VERSION 5.7 ;
  NOWIREEXTENSIONATPIN ON ;
  DIVIDERCHAR "/" ;
  BUSBITCHARS "[]" ;
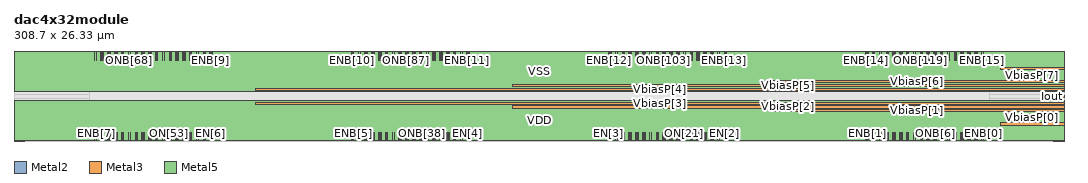
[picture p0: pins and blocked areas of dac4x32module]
MACRO dac4x32module
  CLASS BLOCK ;
  FOREIGN dac4x32module ;
  ORIGIN 0.000 0.070 ;
  SIZE 308.700 BY 26.330 ;
  PIN EN[13]
    ANTENNAGATEAREA 0.039000 ;
    PORT
      LAYER Metal2 ;
        RECT 209.325 23.715 209.525 26.190 ;
    END
  END EN[13]
  PIN ENB[13]
    ANTENNAGATEAREA 0.039000 ;
    PORT
      LAYER Metal2 ;
        RECT 208.775 23.715 208.975 26.190 ;
    END
  END ENB[13]
  PIN ON[111]
    ANTENNAGATEAREA 0.039000 ;
    PORT
      LAYER Metal2 ;
        RECT 207.325 23.715 207.525 26.190 ;
    END
  END ON[111]
  PIN ONB[111]
    ANTENNAGATEAREA 0.039000 ;
    PORT
      LAYER Metal2 ;
        RECT 206.775 23.715 206.975 26.190 ;
    END
  END ONB[111]
  PIN ON[110]
    ANTENNAGATEAREA 0.039000 ;
    PORT
      LAYER Metal2 ;
        RECT 205.325 23.715 205.525 26.190 ;
    END
  END ON[110]
  PIN ONB[110]
    ANTENNAGATEAREA 0.039000 ;
    PORT
      LAYER Metal2 ;
        RECT 204.775 23.715 204.975 26.190 ;
    END
  END ONB[110]
  PIN ON[109]
    ANTENNAGATEAREA 0.039000 ;
    PORT
      LAYER Metal2 ;
        RECT 203.325 23.715 203.525 26.190 ;
    END
  END ON[109]
  PIN ONB[109]
    ANTENNAGATEAREA 0.039000 ;
    PORT
      LAYER Metal2 ;
        RECT 202.775 23.715 202.975 26.190 ;
    END
  END ONB[109]
  PIN ON[108]
    ANTENNAGATEAREA 0.039000 ;
    PORT
      LAYER Metal2 ;
        RECT 201.325 23.715 201.525 26.190 ;
    END
  END ON[108]
  PIN ONB[108]
    ANTENNAGATEAREA 0.039000 ;
    PORT
      LAYER Metal2 ;
        RECT 200.775 23.715 200.975 26.190 ;
    END
  END ONB[108]
  PIN ON[107]
    ANTENNAGATEAREA 0.039000 ;
    PORT
      LAYER Metal2 ;
        RECT 199.325 23.715 199.525 26.190 ;
    END
  END ON[107]
  PIN ONB[107]
    ANTENNAGATEAREA 0.039000 ;
    PORT
      LAYER Metal2 ;
        RECT 198.775 23.715 198.975 26.190 ;
    END
  END ONB[107]
  PIN ON[106]
    ANTENNAGATEAREA 0.039000 ;
    PORT
      LAYER Metal2 ;
        RECT 197.325 23.715 197.525 26.190 ;
    END
  END ON[106]
  PIN ONB[106]
    ANTENNAGATEAREA 0.039000 ;
    PORT
      LAYER Metal2 ;
        RECT 196.775 23.715 196.975 26.190 ;
    END
  END ONB[106]
  PIN ON[105]
    ANTENNAGATEAREA 0.039000 ;
    PORT
      LAYER Metal2 ;
        RECT 195.325 23.715 195.525 26.190 ;
    END
  END ON[105]
  PIN ONB[105]
    ANTENNAGATEAREA 0.039000 ;
    PORT
      LAYER Metal2 ;
        RECT 194.775 23.715 194.975 26.190 ;
    END
  END ONB[105]
  PIN ON[104]
    ANTENNAGATEAREA 0.039000 ;
    PORT
      LAYER Metal2 ;
        RECT 193.325 23.715 193.525 26.190 ;
    END
  END ON[104]
  PIN ONB[104]
    ANTENNAGATEAREA 0.039000 ;
    PORT
      LAYER Metal2 ;
        RECT 192.775 23.715 192.975 26.190 ;
    END
  END ONB[104]
  PIN ON[103]
    ANTENNAGATEAREA 0.039000 ;
    PORT
      LAYER Metal2 ;
        RECT 191.325 23.715 191.525 26.190 ;
    END
  END ON[103]
  PIN ONB[103]
    ANTENNAGATEAREA 0.039000 ;
    PORT
      LAYER Metal2 ;
        RECT 190.775 23.715 190.975 26.190 ;
    END
  END ONB[103]
  PIN ON[102]
    ANTENNAGATEAREA 0.039000 ;
    PORT
      LAYER Metal2 ;
        RECT 189.325 23.715 189.525 26.190 ;
    END
  END ON[102]
  PIN ONB[102]
    ANTENNAGATEAREA 0.039000 ;
    PORT
      LAYER Metal2 ;
        RECT 188.775 23.715 188.975 26.190 ;
    END
  END ONB[102]
  PIN ON[101]
    ANTENNAGATEAREA 0.039000 ;
    PORT
      LAYER Metal2 ;
        RECT 187.325 23.715 187.525 26.190 ;
    END
  END ON[101]
  PIN ONB[101]
    ANTENNAGATEAREA 0.039000 ;
    PORT
      LAYER Metal2 ;
        RECT 186.775 23.715 186.975 26.190 ;
    END
  END ONB[101]
  PIN ON[100]
    ANTENNAGATEAREA 0.039000 ;
    PORT
      LAYER Metal2 ;
        RECT 185.325 23.715 185.525 26.190 ;
    END
  END ON[100]
  PIN ONB[100]
    ANTENNAGATEAREA 0.039000 ;
    PORT
      LAYER Metal2 ;
        RECT 184.775 23.715 184.975 26.190 ;
    END
  END ONB[100]
  PIN ON[99]
    ANTENNAGATEAREA 0.039000 ;
    PORT
      LAYER Metal2 ;
        RECT 183.325 23.715 183.525 26.190 ;
    END
  END ON[99]
  PIN ONB[99]
    ANTENNAGATEAREA 0.039000 ;
    PORT
      LAYER Metal2 ;
        RECT 182.775 23.715 182.975 26.190 ;
    END
  END ONB[99]
  PIN ON[98]
    ANTENNAGATEAREA 0.039000 ;
    PORT
      LAYER Metal2 ;
        RECT 181.325 23.715 181.525 26.190 ;
    END
  END ON[98]
  PIN ONB[98]
    ANTENNAGATEAREA 0.039000 ;
    PORT
      LAYER Metal2 ;
        RECT 180.775 23.715 180.975 26.190 ;
    END
  END ONB[98]
  PIN ON[97]
    ANTENNAGATEAREA 0.039000 ;
    PORT
      LAYER Metal2 ;
        RECT 179.325 23.715 179.525 26.190 ;
    END
  END ON[97]
  PIN ONB[97]
    ANTENNAGATEAREA 0.039000 ;
    PORT
      LAYER Metal2 ;
        RECT 178.775 23.715 178.975 26.190 ;
    END
  END ONB[97]
  PIN ON[96]
    ANTENNAGATEAREA 0.039000 ;
    PORT
      LAYER Metal2 ;
        RECT 177.325 23.715 177.525 26.190 ;
    END
  END ON[96]
  PIN ONB[96]
    ANTENNAGATEAREA 0.039000 ;
    PORT
      LAYER Metal2 ;
        RECT 176.775 23.715 176.975 26.190 ;
    END
  END ONB[96]
  PIN EN[12]
    ANTENNAGATEAREA 0.039000 ;
    PORT
      LAYER Metal2 ;
        RECT 175.325 23.715 175.525 26.190 ;
    END
  END EN[12]
  PIN ENB[12]
    ANTENNAGATEAREA 0.039000 ;
    PORT
      LAYER Metal2 ;
        RECT 174.775 23.715 174.975 26.190 ;
    END
  END ENB[12]
  PIN EN[15]
    ANTENNAGATEAREA 0.039000 ;
    PORT
      LAYER Metal2 ;
        RECT 284.925 23.715 285.125 26.190 ;
    END
  END EN[15]
  PIN ENB[15]
    ANTENNAGATEAREA 0.039000 ;
    PORT
      LAYER Metal2 ;
        RECT 284.375 23.715 284.575 26.190 ;
    END
  END ENB[15]
  PIN ON[127]
    ANTENNAGATEAREA 0.039000 ;
    PORT
      LAYER Metal2 ;
        RECT 282.925 23.715 283.125 26.190 ;
    END
  END ON[127]
  PIN ONB[127]
    ANTENNAGATEAREA 0.039000 ;
    PORT
      LAYER Metal2 ;
        RECT 282.375 23.715 282.575 26.190 ;
    END
  END ONB[127]
  PIN ON[126]
    ANTENNAGATEAREA 0.039000 ;
    PORT
      LAYER Metal2 ;
        RECT 280.925 23.715 281.125 26.190 ;
    END
  END ON[126]
  PIN ONB[126]
    ANTENNAGATEAREA 0.039000 ;
    PORT
      LAYER Metal2 ;
        RECT 280.375 23.715 280.575 26.190 ;
    END
  END ONB[126]
  PIN ON[125]
    ANTENNAGATEAREA 0.039000 ;
    PORT
      LAYER Metal2 ;
        RECT 278.925 23.715 279.125 26.190 ;
    END
  END ON[125]
  PIN ONB[125]
    ANTENNAGATEAREA 0.039000 ;
    PORT
      LAYER Metal2 ;
        RECT 278.375 23.715 278.575 26.190 ;
    END
  END ONB[125]
  PIN ON[124]
    ANTENNAGATEAREA 0.039000 ;
    PORT
      LAYER Metal2 ;
        RECT 276.925 23.715 277.125 26.190 ;
    END
  END ON[124]
  PIN ONB[124]
    ANTENNAGATEAREA 0.039000 ;
    PORT
      LAYER Metal2 ;
        RECT 276.375 23.715 276.575 26.190 ;
    END
  END ONB[124]
  PIN ON[123]
    ANTENNAGATEAREA 0.039000 ;
    PORT
      LAYER Metal2 ;
        RECT 274.925 23.715 275.125 26.190 ;
    END
  END ON[123]
  PIN ONB[123]
    ANTENNAGATEAREA 0.039000 ;
    PORT
      LAYER Metal2 ;
        RECT 274.375 23.715 274.575 26.190 ;
    END
  END ONB[123]
  PIN ON[122]
    ANTENNAGATEAREA 0.039000 ;
    PORT
      LAYER Metal2 ;
        RECT 272.925 23.715 273.125 26.190 ;
    END
  END ON[122]
  PIN ONB[122]
    ANTENNAGATEAREA 0.039000 ;
    PORT
      LAYER Metal2 ;
        RECT 272.375 23.715 272.575 26.190 ;
    END
  END ONB[122]
  PIN ON[121]
    ANTENNAGATEAREA 0.039000 ;
    PORT
      LAYER Metal2 ;
        RECT 270.925 23.715 271.125 26.190 ;
    END
  END ON[121]
  PIN ONB[121]
    ANTENNAGATEAREA 0.039000 ;
    PORT
      LAYER Metal2 ;
        RECT 270.375 23.715 270.575 26.190 ;
    END
  END ONB[121]
  PIN ON[120]
    ANTENNAGATEAREA 0.039000 ;
    PORT
      LAYER Metal2 ;
        RECT 268.925 23.715 269.125 26.190 ;
    END
  END ON[120]
  PIN ONB[120]
    ANTENNAGATEAREA 0.039000 ;
    PORT
      LAYER Metal2 ;
        RECT 268.375 23.715 268.575 26.190 ;
    END
  END ONB[120]
  PIN ON[119]
    ANTENNAGATEAREA 0.039000 ;
    PORT
      LAYER Metal2 ;
        RECT 266.925 23.715 267.125 26.190 ;
    END
  END ON[119]
  PIN ONB[119]
    ANTENNAGATEAREA 0.039000 ;
    PORT
      LAYER Metal2 ;
        RECT 266.375 23.715 266.575 26.190 ;
    END
  END ONB[119]
  PIN ON[118]
    ANTENNAGATEAREA 0.039000 ;
    PORT
      LAYER Metal2 ;
        RECT 264.925 23.715 265.125 26.190 ;
    END
  END ON[118]
  PIN ONB[118]
    ANTENNAGATEAREA 0.039000 ;
    PORT
      LAYER Metal2 ;
        RECT 264.375 23.715 264.575 26.190 ;
    END
  END ONB[118]
  PIN ON[117]
    ANTENNAGATEAREA 0.039000 ;
    PORT
      LAYER Metal2 ;
        RECT 262.925 23.715 263.125 26.190 ;
    END
  END ON[117]
  PIN ONB[117]
    ANTENNAGATEAREA 0.039000 ;
    PORT
      LAYER Metal2 ;
        RECT 262.375 23.715 262.575 26.190 ;
    END
  END ONB[117]
  PIN ON[116]
    ANTENNAGATEAREA 0.039000 ;
    PORT
      LAYER Metal2 ;
        RECT 260.925 23.715 261.125 26.190 ;
    END
  END ON[116]
  PIN ONB[116]
    ANTENNAGATEAREA 0.039000 ;
    PORT
      LAYER Metal2 ;
        RECT 260.375 23.715 260.575 26.190 ;
    END
  END ONB[116]
  PIN ON[115]
    ANTENNAGATEAREA 0.039000 ;
    PORT
      LAYER Metal2 ;
        RECT 258.925 23.715 259.125 26.190 ;
    END
  END ON[115]
  PIN ONB[115]
    ANTENNAGATEAREA 0.039000 ;
    PORT
      LAYER Metal2 ;
        RECT 258.375 23.715 258.575 26.190 ;
    END
  END ONB[115]
  PIN ON[114]
    ANTENNAGATEAREA 0.039000 ;
    PORT
      LAYER Metal2 ;
        RECT 256.925 23.715 257.125 26.190 ;
    END
  END ON[114]
  PIN ONB[114]
    ANTENNAGATEAREA 0.039000 ;
    PORT
      LAYER Metal2 ;
        RECT 256.375 23.715 256.575 26.190 ;
    END
  END ONB[114]
  PIN ON[113]
    ANTENNAGATEAREA 0.039000 ;
    PORT
      LAYER Metal2 ;
        RECT 254.925 23.715 255.125 26.190 ;
    END
  END ON[113]
  PIN ONB[113]
    ANTENNAGATEAREA 0.039000 ;
    PORT
      LAYER Metal2 ;
        RECT 254.375 23.715 254.575 26.190 ;
    END
  END ONB[113]
  PIN ON[112]
    ANTENNAGATEAREA 0.039000 ;
    PORT
      LAYER Metal2 ;
        RECT 252.925 23.715 253.125 26.190 ;
    END
  END ON[112]
  PIN ONB[112]
    ANTENNAGATEAREA 0.039000 ;
    PORT
      LAYER Metal2 ;
        RECT 252.375 23.715 252.575 26.190 ;
    END
  END ONB[112]
  PIN EN[14]
    ANTENNAGATEAREA 0.039000 ;
    PORT
      LAYER Metal2 ;
        RECT 250.925 23.715 251.125 26.190 ;
    END
  END EN[14]
  PIN ENB[14]
    ANTENNAGATEAREA 0.039000 ;
    PORT
      LAYER Metal2 ;
        RECT 250.375 23.715 250.575 26.190 ;
    END
  END ENB[14]
  PIN EN[9]
    ANTENNAGATEAREA 0.039000 ;
    PORT
      LAYER Metal2 ;
        RECT 58.125 23.715 58.325 26.190 ;
    END
  END EN[9]
  PIN ENB[9]
    ANTENNAGATEAREA 0.039000 ;
    PORT
      LAYER Metal2 ;
        RECT 57.575 23.715 57.775 26.190 ;
    END
  END ENB[9]
  PIN ON[79]
    ANTENNAGATEAREA 0.039000 ;
    PORT
      LAYER Metal2 ;
        RECT 56.125 23.715 56.325 26.190 ;
    END
  END ON[79]
  PIN ONB[79]
    ANTENNAGATEAREA 0.039000 ;
    PORT
      LAYER Metal2 ;
        RECT 55.575 23.715 55.775 26.190 ;
    END
  END ONB[79]
  PIN ON[78]
    ANTENNAGATEAREA 0.039000 ;
    PORT
      LAYER Metal2 ;
        RECT 54.125 23.715 54.325 26.190 ;
    END
  END ON[78]
  PIN ONB[78]
    ANTENNAGATEAREA 0.039000 ;
    PORT
      LAYER Metal2 ;
        RECT 53.575 23.715 53.775 26.190 ;
    END
  END ONB[78]
  PIN ON[77]
    ANTENNAGATEAREA 0.039000 ;
    PORT
      LAYER Metal2 ;
        RECT 52.125 23.715 52.325 26.190 ;
    END
  END ON[77]
  PIN ONB[77]
    ANTENNAGATEAREA 0.039000 ;
    PORT
      LAYER Metal2 ;
        RECT 51.575 23.715 51.775 26.190 ;
    END
  END ONB[77]
  PIN ON[76]
    ANTENNAGATEAREA 0.039000 ;
    PORT
      LAYER Metal2 ;
        RECT 50.125 23.715 50.325 26.190 ;
    END
  END ON[76]
  PIN ONB[76]
    ANTENNAGATEAREA 0.039000 ;
    PORT
      LAYER Metal2 ;
        RECT 49.575 23.715 49.775 26.190 ;
    END
  END ONB[76]
  PIN ON[75]
    ANTENNAGATEAREA 0.039000 ;
    PORT
      LAYER Metal2 ;
        RECT 48.125 23.715 48.325 26.190 ;
    END
  END ON[75]
  PIN ONB[75]
    ANTENNAGATEAREA 0.039000 ;
    PORT
      LAYER Metal2 ;
        RECT 47.575 23.715 47.775 26.190 ;
    END
  END ONB[75]
  PIN ON[74]
    ANTENNAGATEAREA 0.039000 ;
    PORT
      LAYER Metal2 ;
        RECT 46.125 23.715 46.325 26.190 ;
    END
  END ON[74]
  PIN ONB[74]
    ANTENNAGATEAREA 0.039000 ;
    PORT
      LAYER Metal2 ;
        RECT 45.575 23.715 45.775 26.190 ;
    END
  END ONB[74]
  PIN ON[73]
    ANTENNAGATEAREA 0.039000 ;
    PORT
      LAYER Metal2 ;
        RECT 44.125 23.715 44.325 26.190 ;
    END
  END ON[73]
  PIN ONB[73]
    ANTENNAGATEAREA 0.039000 ;
    PORT
      LAYER Metal2 ;
        RECT 43.575 23.715 43.775 26.190 ;
    END
  END ONB[73]
  PIN ON[72]
    ANTENNAGATEAREA 0.039000 ;
    PORT
      LAYER Metal2 ;
        RECT 42.125 23.715 42.325 26.190 ;
    END
  END ON[72]
  PIN ONB[72]
    ANTENNAGATEAREA 0.039000 ;
    PORT
      LAYER Metal2 ;
        RECT 41.575 23.715 41.775 26.190 ;
    END
  END ONB[72]
  PIN ON[71]
    ANTENNAGATEAREA 0.039000 ;
    PORT
      LAYER Metal2 ;
        RECT 40.125 23.715 40.325 26.190 ;
    END
  END ON[71]
  PIN ONB[71]
    ANTENNAGATEAREA 0.039000 ;
    PORT
      LAYER Metal2 ;
        RECT 39.575 23.715 39.775 26.190 ;
    END
  END ONB[71]
  PIN ON[70]
    ANTENNAGATEAREA 0.039000 ;
    PORT
      LAYER Metal2 ;
        RECT 38.125 23.715 38.325 26.190 ;
    END
  END ON[70]
  PIN ONB[70]
    ANTENNAGATEAREA 0.039000 ;
    PORT
      LAYER Metal2 ;
        RECT 37.575 23.715 37.775 26.190 ;
    END
  END ONB[70]
  PIN ON[69]
    ANTENNAGATEAREA 0.039000 ;
    PORT
      LAYER Metal2 ;
        RECT 36.125 23.715 36.325 26.190 ;
    END
  END ON[69]
  PIN ONB[69]
    ANTENNAGATEAREA 0.039000 ;
    PORT
      LAYER Metal2 ;
        RECT 35.575 23.715 35.775 26.190 ;
    END
  END ONB[69]
  PIN ON[68]
    ANTENNAGATEAREA 0.039000 ;
    PORT
      LAYER Metal2 ;
        RECT 34.125 23.715 34.325 26.190 ;
    END
  END ON[68]
  PIN ONB[68]
    ANTENNAGATEAREA 0.039000 ;
    PORT
      LAYER Metal2 ;
        RECT 33.575 23.715 33.775 26.190 ;
    END
  END ONB[68]
  PIN ON[67]
    ANTENNAGATEAREA 0.039000 ;
    PORT
      LAYER Metal2 ;
        RECT 32.125 23.715 32.325 26.190 ;
    END
  END ON[67]
  PIN ONB[67]
    ANTENNAGATEAREA 0.039000 ;
    PORT
      LAYER Metal2 ;
        RECT 31.575 23.715 31.775 26.190 ;
    END
  END ONB[67]
  PIN ON[66]
    ANTENNAGATEAREA 0.039000 ;
    PORT
      LAYER Metal2 ;
        RECT 30.125 23.715 30.325 26.190 ;
    END
  END ON[66]
  PIN ONB[66]
    ANTENNAGATEAREA 0.039000 ;
    PORT
      LAYER Metal2 ;
        RECT 29.575 23.715 29.775 26.190 ;
    END
  END ONB[66]
  PIN ON[65]
    ANTENNAGATEAREA 0.039000 ;
    PORT
      LAYER Metal2 ;
        RECT 28.125 23.715 28.325 26.190 ;
    END
  END ON[65]
  PIN ONB[65]
    ANTENNAGATEAREA 0.039000 ;
    PORT
      LAYER Metal2 ;
        RECT 27.575 23.715 27.775 26.190 ;
    END
  END ONB[65]
  PIN ON[64]
    ANTENNAGATEAREA 0.039000 ;
    PORT
      LAYER Metal2 ;
        RECT 26.125 23.715 26.325 26.190 ;
    END
  END ON[64]
  PIN ONB[64]
    ANTENNAGATEAREA 0.039000 ;
    PORT
      LAYER Metal2 ;
        RECT 25.575 23.715 25.775 26.190 ;
    END
  END ONB[64]
  PIN EN[8]
    ANTENNAGATEAREA 0.039000 ;
    PORT
      LAYER Metal2 ;
        RECT 24.125 23.715 24.325 26.190 ;
    END
  END EN[8]
  PIN ENB[8]
    ANTENNAGATEAREA 0.039000 ;
    PORT
      LAYER Metal2 ;
        RECT 23.575 23.715 23.775 26.190 ;
    END
  END ENB[8]
  PIN EN[11]
    ANTENNAGATEAREA 0.039000 ;
    PORT
      LAYER Metal2 ;
        RECT 133.725 23.715 133.925 26.190 ;
    END
  END EN[11]
  PIN ENB[11]
    ANTENNAGATEAREA 0.039000 ;
    PORT
      LAYER Metal2 ;
        RECT 133.175 23.715 133.375 26.190 ;
    END
  END ENB[11]
  PIN ON[95]
    ANTENNAGATEAREA 0.039000 ;
    PORT
      LAYER Metal2 ;
        RECT 131.725 23.715 131.925 26.190 ;
    END
  END ON[95]
  PIN ONB[95]
    ANTENNAGATEAREA 0.039000 ;
    PORT
      LAYER Metal2 ;
        RECT 131.175 23.715 131.375 26.190 ;
    END
  END ONB[95]
  PIN ON[94]
    ANTENNAGATEAREA 0.039000 ;
    PORT
      LAYER Metal2 ;
        RECT 129.725 23.715 129.925 26.190 ;
    END
  END ON[94]
  PIN ONB[94]
    ANTENNAGATEAREA 0.039000 ;
    PORT
      LAYER Metal2 ;
        RECT 129.175 23.715 129.375 26.190 ;
    END
  END ONB[94]
  PIN ON[93]
    ANTENNAGATEAREA 0.039000 ;
    PORT
      LAYER Metal2 ;
        RECT 127.725 23.715 127.925 26.190 ;
    END
  END ON[93]
  PIN ONB[93]
    ANTENNAGATEAREA 0.039000 ;
    PORT
      LAYER Metal2 ;
        RECT 127.175 23.715 127.375 26.190 ;
    END
  END ONB[93]
  PIN ON[92]
    ANTENNAGATEAREA 0.039000 ;
    PORT
      LAYER Metal2 ;
        RECT 125.725 23.715 125.925 26.190 ;
    END
  END ON[92]
  PIN ONB[92]
    ANTENNAGATEAREA 0.039000 ;
    PORT
      LAYER Metal2 ;
        RECT 125.175 23.715 125.375 26.190 ;
    END
  END ONB[92]
  PIN ON[91]
    ANTENNAGATEAREA 0.039000 ;
    PORT
      LAYER Metal2 ;
        RECT 123.725 23.715 123.925 26.190 ;
    END
  END ON[91]
  PIN ONB[91]
    ANTENNAGATEAREA 0.039000 ;
    PORT
      LAYER Metal2 ;
        RECT 123.175 23.715 123.375 26.190 ;
    END
  END ONB[91]
  PIN ON[90]
    ANTENNAGATEAREA 0.039000 ;
    PORT
      LAYER Metal2 ;
        RECT 121.725 23.715 121.925 26.190 ;
    END
  END ON[90]
  PIN ONB[90]
    ANTENNAGATEAREA 0.039000 ;
    PORT
      LAYER Metal2 ;
        RECT 121.175 23.715 121.375 26.190 ;
    END
  END ONB[90]
  PIN ON[89]
    ANTENNAGATEAREA 0.039000 ;
    PORT
      LAYER Metal2 ;
        RECT 119.725 23.715 119.925 26.190 ;
    END
  END ON[89]
  PIN ONB[89]
    ANTENNAGATEAREA 0.039000 ;
    PORT
      LAYER Metal2 ;
        RECT 119.175 23.715 119.375 26.190 ;
    END
  END ONB[89]
  PIN ON[88]
    ANTENNAGATEAREA 0.039000 ;
    PORT
      LAYER Metal2 ;
        RECT 117.725 23.715 117.925 26.190 ;
    END
  END ON[88]
  PIN ONB[88]
    ANTENNAGATEAREA 0.039000 ;
    PORT
      LAYER Metal2 ;
        RECT 117.175 23.715 117.375 26.190 ;
    END
  END ONB[88]
  PIN ON[87]
    ANTENNAGATEAREA 0.039000 ;
    PORT
      LAYER Metal2 ;
        RECT 115.725 23.715 115.925 26.190 ;
    END
  END ON[87]
  PIN ONB[87]
    ANTENNAGATEAREA 0.039000 ;
    PORT
      LAYER Metal2 ;
        RECT 115.175 23.715 115.375 26.190 ;
    END
  END ONB[87]
  PIN ON[86]
    ANTENNAGATEAREA 0.039000 ;
    PORT
      LAYER Metal2 ;
        RECT 113.725 23.715 113.925 26.190 ;
    END
  END ON[86]
  PIN ONB[86]
    ANTENNAGATEAREA 0.039000 ;
    PORT
      LAYER Metal2 ;
        RECT 113.175 23.715 113.375 26.190 ;
    END
  END ONB[86]
  PIN ON[85]
    ANTENNAGATEAREA 0.039000 ;
    PORT
      LAYER Metal2 ;
        RECT 111.725 23.715 111.925 26.190 ;
    END
  END ON[85]
  PIN ONB[85]
    ANTENNAGATEAREA 0.039000 ;
    PORT
      LAYER Metal2 ;
        RECT 111.175 23.715 111.375 26.190 ;
    END
  END ONB[85]
  PIN ON[84]
    ANTENNAGATEAREA 0.039000 ;
    PORT
      LAYER Metal2 ;
        RECT 109.725 23.715 109.925 26.190 ;
    END
  END ON[84]
  PIN ONB[84]
    ANTENNAGATEAREA 0.039000 ;
    PORT
      LAYER Metal2 ;
        RECT 109.175 23.715 109.375 26.190 ;
    END
  END ONB[84]
  PIN ON[83]
    ANTENNAGATEAREA 0.039000 ;
    PORT
      LAYER Metal2 ;
        RECT 107.725 23.715 107.925 26.190 ;
    END
  END ON[83]
  PIN ONB[83]
    ANTENNAGATEAREA 0.039000 ;
    PORT
      LAYER Metal2 ;
        RECT 107.175 23.715 107.375 26.190 ;
    END
  END ONB[83]
  PIN ON[82]
    ANTENNAGATEAREA 0.039000 ;
    PORT
      LAYER Metal2 ;
        RECT 105.725 23.715 105.925 26.190 ;
    END
  END ON[82]
  PIN ONB[82]
    ANTENNAGATEAREA 0.039000 ;
    PORT
      LAYER Metal2 ;
        RECT 105.175 23.715 105.375 26.190 ;
    END
  END ONB[82]
  PIN ON[81]
    ANTENNAGATEAREA 0.039000 ;
    PORT
      LAYER Metal2 ;
        RECT 103.725 23.715 103.925 26.190 ;
    END
  END ON[81]
  PIN ONB[81]
    ANTENNAGATEAREA 0.039000 ;
    PORT
      LAYER Metal2 ;
        RECT 103.175 23.715 103.375 26.190 ;
    END
  END ONB[81]
  PIN ON[80]
    ANTENNAGATEAREA 0.039000 ;
    PORT
      LAYER Metal2 ;
        RECT 101.725 23.715 101.925 26.190 ;
    END
  END ON[80]
  PIN ONB[80]
    ANTENNAGATEAREA 0.039000 ;
    PORT
      LAYER Metal2 ;
        RECT 101.175 23.715 101.375 26.190 ;
    END
  END ONB[80]
  PIN EN[10]
    ANTENNAGATEAREA 0.039000 ;
    PORT
      LAYER Metal2 ;
        RECT 99.725 23.715 99.925 26.190 ;
    END
  END EN[10]
  PIN ENB[10]
    ANTENNAGATEAREA 0.039000 ;
    PORT
      LAYER Metal2 ;
        RECT 99.175 23.715 99.375 26.190 ;
    END
  END ENB[10]
  PIN EN[4]
    ANTENNAGATEAREA 0.039000 ;
    PORT
      LAYER Metal2 ;
        RECT 133.175 0.000 133.375 2.475 ;
    END
  END EN[4]
  PIN ENB[4]
    ANTENNAGATEAREA 0.039000 ;
    PORT
      LAYER Metal2 ;
        RECT 133.725 0.000 133.925 2.475 ;
    END
  END ENB[4]
  PIN EN[6]
    ANTENNAGATEAREA 0.039000 ;
    PORT
      LAYER Metal2 ;
        RECT 57.575 0.000 57.775 2.475 ;
    END
  END EN[6]
  PIN ENB[6]
    ANTENNAGATEAREA 0.039000 ;
    PORT
      LAYER Metal2 ;
        RECT 58.125 0.000 58.325 2.475 ;
    END
  END ENB[6]
  PIN ON[63]
    ANTENNAGATEAREA 0.039000 ;
    PORT
      LAYER Metal2 ;
        RECT 25.575 0.000 25.775 2.475 ;
    END
  END ON[63]
  PIN ONB[63]
    ANTENNAGATEAREA 0.039000 ;
    PORT
      LAYER Metal2 ;
        RECT 26.125 0.000 26.325 2.475 ;
    END
  END ONB[63]
  PIN ON[62]
    ANTENNAGATEAREA 0.039000 ;
    PORT
      LAYER Metal2 ;
        RECT 27.575 0.000 27.775 2.475 ;
    END
  END ON[62]
  PIN ONB[62]
    ANTENNAGATEAREA 0.039000 ;
    PORT
      LAYER Metal2 ;
        RECT 28.125 0.000 28.325 2.475 ;
    END
  END ONB[62]
  PIN ON[61]
    ANTENNAGATEAREA 0.039000 ;
    PORT
      LAYER Metal2 ;
        RECT 29.575 0.000 29.775 2.475 ;
    END
  END ON[61]
  PIN ONB[61]
    ANTENNAGATEAREA 0.039000 ;
    PORT
      LAYER Metal2 ;
        RECT 30.125 0.000 30.325 2.475 ;
    END
  END ONB[61]
  PIN ON[60]
    ANTENNAGATEAREA 0.039000 ;
    PORT
      LAYER Metal2 ;
        RECT 31.575 0.000 31.775 2.475 ;
    END
  END ON[60]
  PIN ONB[60]
    ANTENNAGATEAREA 0.039000 ;
    PORT
      LAYER Metal2 ;
        RECT 32.125 0.000 32.325 2.475 ;
    END
  END ONB[60]
  PIN ON[59]
    ANTENNAGATEAREA 0.039000 ;
    PORT
      LAYER Metal2 ;
        RECT 33.575 0.000 33.775 2.475 ;
    END
  END ON[59]
  PIN ONB[59]
    ANTENNAGATEAREA 0.039000 ;
    PORT
      LAYER Metal2 ;
        RECT 34.125 0.000 34.325 2.475 ;
    END
  END ONB[59]
  PIN ON[58]
    ANTENNAGATEAREA 0.039000 ;
    PORT
      LAYER Metal2 ;
        RECT 35.575 0.000 35.775 2.475 ;
    END
  END ON[58]
  PIN ONB[58]
    ANTENNAGATEAREA 0.039000 ;
    PORT
      LAYER Metal2 ;
        RECT 36.125 0.000 36.325 2.475 ;
    END
  END ONB[58]
  PIN ON[57]
    ANTENNAGATEAREA 0.039000 ;
    PORT
      LAYER Metal2 ;
        RECT 37.575 0.000 37.775 2.475 ;
    END
  END ON[57]
  PIN EN[7]
    ANTENNAGATEAREA 0.039000 ;
    PORT
      LAYER Metal2 ;
        RECT 23.575 0.000 23.775 2.475 ;
    END
  END EN[7]
  PIN ENB[7]
    ANTENNAGATEAREA 0.039000 ;
    PORT
      LAYER Metal2 ;
        RECT 24.125 0.000 24.325 2.475 ;
    END
  END ENB[7]
  PIN ONB[57]
    ANTENNAGATEAREA 0.039000 ;
    PORT
      LAYER Metal2 ;
        RECT 38.125 0.000 38.325 2.475 ;
    END
  END ONB[57]
  PIN ON[56]
    ANTENNAGATEAREA 0.039000 ;
    PORT
      LAYER Metal2 ;
        RECT 39.575 0.000 39.775 2.475 ;
    END
  END ON[56]
  PIN ONB[56]
    ANTENNAGATEAREA 0.039000 ;
    PORT
      LAYER Metal2 ;
        RECT 40.125 0.000 40.325 2.475 ;
    END
  END ONB[56]
  PIN ON[55]
    ANTENNAGATEAREA 0.039000 ;
    PORT
      LAYER Metal2 ;
        RECT 41.575 0.000 41.775 2.475 ;
    END
  END ON[55]
  PIN ONB[55]
    ANTENNAGATEAREA 0.039000 ;
    PORT
      LAYER Metal2 ;
        RECT 42.125 0.000 42.325 2.475 ;
    END
  END ONB[55]
  PIN ON[54]
    ANTENNAGATEAREA 0.039000 ;
    PORT
      LAYER Metal2 ;
        RECT 43.575 0.000 43.775 2.475 ;
    END
  END ON[54]
  PIN ONB[54]
    ANTENNAGATEAREA 0.039000 ;
    PORT
      LAYER Metal2 ;
        RECT 44.125 0.000 44.325 2.475 ;
    END
  END ONB[54]
  PIN ON[53]
    ANTENNAGATEAREA 0.039000 ;
    PORT
      LAYER Metal2 ;
        RECT 45.575 0.000 45.775 2.475 ;
    END
  END ON[53]
  PIN ONB[53]
    ANTENNAGATEAREA 0.039000 ;
    PORT
      LAYER Metal2 ;
        RECT 46.125 0.000 46.325 2.475 ;
    END
  END ONB[53]
  PIN ON[52]
    ANTENNAGATEAREA 0.039000 ;
    PORT
      LAYER Metal2 ;
        RECT 47.575 0.000 47.775 2.475 ;
    END
  END ON[52]
  PIN ONB[52]
    ANTENNAGATEAREA 0.039000 ;
    PORT
      LAYER Metal2 ;
        RECT 48.125 0.000 48.325 2.475 ;
    END
  END ONB[52]
  PIN ON[51]
    ANTENNAGATEAREA 0.039000 ;
    PORT
      LAYER Metal2 ;
        RECT 49.575 0.000 49.775 2.475 ;
    END
  END ON[51]
  PIN ONB[51]
    ANTENNAGATEAREA 0.039000 ;
    PORT
      LAYER Metal2 ;
        RECT 50.125 0.000 50.325 2.475 ;
    END
  END ONB[51]
  PIN ON[50]
    ANTENNAGATEAREA 0.039000 ;
    PORT
      LAYER Metal2 ;
        RECT 51.575 0.000 51.775 2.475 ;
    END
  END ON[50]
  PIN ONB[50]
    ANTENNAGATEAREA 0.039000 ;
    PORT
      LAYER Metal2 ;
        RECT 52.125 0.000 52.325 2.475 ;
    END
  END ONB[50]
  PIN ON[49]
    ANTENNAGATEAREA 0.039000 ;
    PORT
      LAYER Metal2 ;
        RECT 53.575 0.000 53.775 2.475 ;
    END
  END ON[49]
  PIN ONB[49]
    ANTENNAGATEAREA 0.039000 ;
    PORT
      LAYER Metal2 ;
        RECT 54.125 0.000 54.325 2.475 ;
    END
  END ONB[49]
  PIN ON[48]
    ANTENNAGATEAREA 0.039000 ;
    PORT
      LAYER Metal2 ;
        RECT 55.575 0.000 55.775 2.475 ;
    END
  END ON[48]
  PIN ONB[48]
    ANTENNAGATEAREA 0.039000 ;
    PORT
      LAYER Metal2 ;
        RECT 56.125 0.000 56.325 2.475 ;
    END
  END ONB[48]
  PIN ON[47]
    ANTENNAGATEAREA 0.039000 ;
    PORT
      LAYER Metal2 ;
        RECT 101.175 0.000 101.375 2.475 ;
    END
  END ON[47]
  PIN ONB[47]
    ANTENNAGATEAREA 0.039000 ;
    PORT
      LAYER Metal2 ;
        RECT 101.725 0.000 101.925 2.475 ;
    END
  END ONB[47]
  PIN ON[46]
    ANTENNAGATEAREA 0.039000 ;
    PORT
      LAYER Metal2 ;
        RECT 103.175 0.000 103.375 2.475 ;
    END
  END ON[46]
  PIN ONB[46]
    ANTENNAGATEAREA 0.039000 ;
    PORT
      LAYER Metal2 ;
        RECT 103.725 0.000 103.925 2.475 ;
    END
  END ONB[46]
  PIN ON[45]
    ANTENNAGATEAREA 0.039000 ;
    PORT
      LAYER Metal2 ;
        RECT 105.175 0.000 105.375 2.475 ;
    END
  END ON[45]
  PIN ONB[45]
    ANTENNAGATEAREA 0.039000 ;
    PORT
      LAYER Metal2 ;
        RECT 105.725 0.000 105.925 2.475 ;
    END
  END ONB[45]
  PIN ON[44]
    ANTENNAGATEAREA 0.039000 ;
    PORT
      LAYER Metal2 ;
        RECT 107.175 0.000 107.375 2.475 ;
    END
  END ON[44]
  PIN ONB[44]
    ANTENNAGATEAREA 0.039000 ;
    PORT
      LAYER Metal2 ;
        RECT 107.725 0.000 107.925 2.475 ;
    END
  END ONB[44]
  PIN ON[43]
    ANTENNAGATEAREA 0.039000 ;
    PORT
      LAYER Metal2 ;
        RECT 109.175 0.000 109.375 2.475 ;
    END
  END ON[43]
  PIN ONB[43]
    ANTENNAGATEAREA 0.039000 ;
    PORT
      LAYER Metal2 ;
        RECT 109.725 0.000 109.925 2.475 ;
    END
  END ONB[43]
  PIN ON[42]
    ANTENNAGATEAREA 0.039000 ;
    PORT
      LAYER Metal2 ;
        RECT 111.175 0.000 111.375 2.475 ;
    END
  END ON[42]
  PIN ONB[42]
    ANTENNAGATEAREA 0.039000 ;
    PORT
      LAYER Metal2 ;
        RECT 111.725 0.000 111.925 2.475 ;
    END
  END ONB[42]
  PIN ON[41]
    ANTENNAGATEAREA 0.039000 ;
    PORT
      LAYER Metal2 ;
        RECT 113.175 0.000 113.375 2.475 ;
    END
  END ON[41]
  PIN EN[5]
    ANTENNAGATEAREA 0.039000 ;
    PORT
      LAYER Metal2 ;
        RECT 99.175 0.000 99.375 2.475 ;
    END
  END EN[5]
  PIN ENB[5]
    ANTENNAGATEAREA 0.039000 ;
    PORT
      LAYER Metal2 ;
        RECT 99.725 0.000 99.925 2.475 ;
    END
  END ENB[5]
  PIN ONB[41]
    ANTENNAGATEAREA 0.039000 ;
    PORT
      LAYER Metal2 ;
        RECT 113.725 0.000 113.925 2.475 ;
    END
  END ONB[41]
  PIN ON[40]
    ANTENNAGATEAREA 0.039000 ;
    PORT
      LAYER Metal2 ;
        RECT 115.175 0.000 115.375 2.475 ;
    END
  END ON[40]
  PIN ONB[40]
    ANTENNAGATEAREA 0.039000 ;
    PORT
      LAYER Metal2 ;
        RECT 115.725 0.000 115.925 2.475 ;
    END
  END ONB[40]
  PIN ON[39]
    ANTENNAGATEAREA 0.039000 ;
    PORT
      LAYER Metal2 ;
        RECT 117.175 0.000 117.375 2.475 ;
    END
  END ON[39]
  PIN ONB[39]
    ANTENNAGATEAREA 0.039000 ;
    PORT
      LAYER Metal2 ;
        RECT 117.725 0.000 117.925 2.475 ;
    END
  END ONB[39]
  PIN ON[38]
    ANTENNAGATEAREA 0.039000 ;
    PORT
      LAYER Metal2 ;
        RECT 119.175 0.000 119.375 2.475 ;
    END
  END ON[38]
  PIN ONB[38]
    ANTENNAGATEAREA 0.039000 ;
    PORT
      LAYER Metal2 ;
        RECT 119.725 0.000 119.925 2.475 ;
    END
  END ONB[38]
  PIN ON[37]
    ANTENNAGATEAREA 0.039000 ;
    PORT
      LAYER Metal2 ;
        RECT 121.175 0.000 121.375 2.475 ;
    END
  END ON[37]
  PIN ONB[37]
    ANTENNAGATEAREA 0.039000 ;
    PORT
      LAYER Metal2 ;
        RECT 121.725 0.000 121.925 2.475 ;
    END
  END ONB[37]
  PIN ON[36]
    ANTENNAGATEAREA 0.039000 ;
    PORT
      LAYER Metal2 ;
        RECT 123.175 0.000 123.375 2.475 ;
    END
  END ON[36]
  PIN ONB[36]
    ANTENNAGATEAREA 0.039000 ;
    PORT
      LAYER Metal2 ;
        RECT 123.725 0.000 123.925 2.475 ;
    END
  END ONB[36]
  PIN ON[35]
    ANTENNAGATEAREA 0.039000 ;
    PORT
      LAYER Metal2 ;
        RECT 125.175 0.000 125.375 2.475 ;
    END
  END ON[35]
  PIN ONB[35]
    ANTENNAGATEAREA 0.039000 ;
    PORT
      LAYER Metal2 ;
        RECT 125.725 0.000 125.925 2.475 ;
    END
  END ONB[35]
  PIN ON[34]
    ANTENNAGATEAREA 0.039000 ;
    PORT
      LAYER Metal2 ;
        RECT 127.175 0.000 127.375 2.475 ;
    END
  END ON[34]
  PIN ONB[34]
    ANTENNAGATEAREA 0.039000 ;
    PORT
      LAYER Metal2 ;
        RECT 127.725 0.000 127.925 2.475 ;
    END
  END ONB[34]
  PIN ON[33]
    ANTENNAGATEAREA 0.039000 ;
    PORT
      LAYER Metal2 ;
        RECT 129.175 0.000 129.375 2.475 ;
    END
  END ON[33]
  PIN ONB[33]
    ANTENNAGATEAREA 0.039000 ;
    PORT
      LAYER Metal2 ;
        RECT 129.725 0.000 129.925 2.475 ;
    END
  END ONB[33]
  PIN ON[32]
    ANTENNAGATEAREA 0.039000 ;
    PORT
      LAYER Metal2 ;
        RECT 131.175 0.000 131.375 2.475 ;
    END
  END ON[32]
  PIN ONB[32]
    ANTENNAGATEAREA 0.039000 ;
    PORT
      LAYER Metal2 ;
        RECT 131.725 0.000 131.925 2.475 ;
    END
  END ONB[32]
  PIN EN[0]
    ANTENNAGATEAREA 0.039000 ;
    PORT
      LAYER Metal2 ;
        RECT 284.375 0.000 284.575 2.475 ;
    END
  END EN[0]
  PIN ENB[0]
    ANTENNAGATEAREA 0.039000 ;
    PORT
      LAYER Metal2 ;
        RECT 284.925 0.000 285.125 2.475 ;
    END
  END ENB[0]
  PIN EN[2]
    ANTENNAGATEAREA 0.039000 ;
    PORT
      LAYER Metal2 ;
        RECT 208.775 0.000 208.975 2.475 ;
    END
  END EN[2]
  PIN ENB[2]
    ANTENNAGATEAREA 0.039000 ;
    PORT
      LAYER Metal2 ;
        RECT 209.325 0.000 209.525 2.475 ;
    END
  END ENB[2]
  PIN ON[31]
    ANTENNAGATEAREA 0.039000 ;
    PORT
      LAYER Metal2 ;
        RECT 176.775 0.000 176.975 2.475 ;
    END
  END ON[31]
  PIN ONB[31]
    ANTENNAGATEAREA 0.039000 ;
    PORT
      LAYER Metal2 ;
        RECT 177.325 0.000 177.525 2.475 ;
    END
  END ONB[31]
  PIN ON[30]
    ANTENNAGATEAREA 0.039000 ;
    PORT
      LAYER Metal2 ;
        RECT 178.775 0.000 178.975 2.475 ;
    END
  END ON[30]
  PIN ONB[30]
    ANTENNAGATEAREA 0.039000 ;
    PORT
      LAYER Metal2 ;
        RECT 179.325 0.000 179.525 2.475 ;
    END
  END ONB[30]
  PIN ON[29]
    ANTENNAGATEAREA 0.039000 ;
    PORT
      LAYER Metal2 ;
        RECT 180.775 0.000 180.975 2.475 ;
    END
  END ON[29]
  PIN ONB[29]
    ANTENNAGATEAREA 0.039000 ;
    PORT
      LAYER Metal2 ;
        RECT 181.325 0.000 181.525 2.475 ;
    END
  END ONB[29]
  PIN ON[28]
    ANTENNAGATEAREA 0.039000 ;
    PORT
      LAYER Metal2 ;
        RECT 182.775 0.000 182.975 2.475 ;
    END
  END ON[28]
  PIN ONB[28]
    ANTENNAGATEAREA 0.039000 ;
    PORT
      LAYER Metal2 ;
        RECT 183.325 0.000 183.525 2.475 ;
    END
  END ONB[28]
  PIN ON[27]
    ANTENNAGATEAREA 0.039000 ;
    PORT
      LAYER Metal2 ;
        RECT 184.775 0.000 184.975 2.475 ;
    END
  END ON[27]
  PIN ONB[27]
    ANTENNAGATEAREA 0.039000 ;
    PORT
      LAYER Metal2 ;
        RECT 185.325 0.000 185.525 2.475 ;
    END
  END ONB[27]
  PIN ON[26]
    ANTENNAGATEAREA 0.039000 ;
    PORT
      LAYER Metal2 ;
        RECT 186.775 0.000 186.975 2.475 ;
    END
  END ON[26]
  PIN ONB[26]
    ANTENNAGATEAREA 0.039000 ;
    PORT
      LAYER Metal2 ;
        RECT 187.325 0.000 187.525 2.475 ;
    END
  END ONB[26]
  PIN ON[25]
    ANTENNAGATEAREA 0.039000 ;
    PORT
      LAYER Metal2 ;
        RECT 188.775 0.000 188.975 2.475 ;
    END
  END ON[25]
  PIN EN[3]
    ANTENNAGATEAREA 0.039000 ;
    PORT
      LAYER Metal2 ;
        RECT 174.775 0.000 174.975 2.475 ;
    END
  END EN[3]
  PIN ENB[3]
    ANTENNAGATEAREA 0.039000 ;
    PORT
      LAYER Metal2 ;
        RECT 175.325 0.000 175.525 2.475 ;
    END
  END ENB[3]
  PIN ONB[25]
    ANTENNAGATEAREA 0.039000 ;
    PORT
      LAYER Metal2 ;
        RECT 189.325 0.000 189.525 2.475 ;
    END
  END ONB[25]
  PIN ON[24]
    ANTENNAGATEAREA 0.039000 ;
    PORT
      LAYER Metal2 ;
        RECT 190.775 0.000 190.975 2.475 ;
    END
  END ON[24]
  PIN ONB[24]
    ANTENNAGATEAREA 0.039000 ;
    PORT
      LAYER Metal2 ;
        RECT 191.325 0.000 191.525 2.475 ;
    END
  END ONB[24]
  PIN ON[23]
    ANTENNAGATEAREA 0.039000 ;
    PORT
      LAYER Metal2 ;
        RECT 192.775 0.000 192.975 2.475 ;
    END
  END ON[23]
  PIN ONB[23]
    ANTENNAGATEAREA 0.039000 ;
    PORT
      LAYER Metal2 ;
        RECT 193.325 0.000 193.525 2.475 ;
    END
  END ONB[23]
  PIN ON[22]
    ANTENNAGATEAREA 0.039000 ;
    PORT
      LAYER Metal2 ;
        RECT 194.775 0.000 194.975 2.475 ;
    END
  END ON[22]
  PIN ONB[22]
    ANTENNAGATEAREA 0.039000 ;
    PORT
      LAYER Metal2 ;
        RECT 195.325 0.000 195.525 2.475 ;
    END
  END ONB[22]
  PIN ON[21]
    ANTENNAGATEAREA 0.039000 ;
    PORT
      LAYER Metal2 ;
        RECT 196.775 0.000 196.975 2.475 ;
    END
  END ON[21]
  PIN ONB[21]
    ANTENNAGATEAREA 0.039000 ;
    PORT
      LAYER Metal2 ;
        RECT 197.325 0.000 197.525 2.475 ;
    END
  END ONB[21]
  PIN ON[20]
    ANTENNAGATEAREA 0.039000 ;
    PORT
      LAYER Metal2 ;
        RECT 198.775 0.000 198.975 2.475 ;
    END
  END ON[20]
  PIN ONB[20]
    ANTENNAGATEAREA 0.039000 ;
    PORT
      LAYER Metal2 ;
        RECT 199.325 0.000 199.525 2.475 ;
    END
  END ONB[20]
  PIN ON[19]
    ANTENNAGATEAREA 0.039000 ;
    PORT
      LAYER Metal2 ;
        RECT 200.775 0.000 200.975 2.475 ;
    END
  END ON[19]
  PIN ONB[19]
    ANTENNAGATEAREA 0.039000 ;
    PORT
      LAYER Metal2 ;
        RECT 201.325 0.000 201.525 2.475 ;
    END
  END ONB[19]
  PIN ON[18]
    ANTENNAGATEAREA 0.039000 ;
    PORT
      LAYER Metal2 ;
        RECT 202.775 0.000 202.975 2.475 ;
    END
  END ON[18]
  PIN ONB[18]
    ANTENNAGATEAREA 0.039000 ;
    PORT
      LAYER Metal2 ;
        RECT 203.325 0.000 203.525 2.475 ;
    END
  END ONB[18]
  PIN ON[17]
    ANTENNAGATEAREA 0.039000 ;
    PORT
      LAYER Metal2 ;
        RECT 204.775 0.000 204.975 2.475 ;
    END
  END ON[17]
  PIN ONB[17]
    ANTENNAGATEAREA 0.039000 ;
    PORT
      LAYER Metal2 ;
        RECT 205.325 0.000 205.525 2.475 ;
    END
  END ONB[17]
  PIN ON[16]
    ANTENNAGATEAREA 0.039000 ;
    PORT
      LAYER Metal2 ;
        RECT 206.775 0.000 206.975 2.475 ;
    END
  END ON[16]
  PIN ONB[16]
    ANTENNAGATEAREA 0.039000 ;
    PORT
      LAYER Metal2 ;
        RECT 207.325 0.000 207.525 2.475 ;
    END
  END ONB[16]
  PIN ON[15]
    ANTENNAGATEAREA 0.039000 ;
    PORT
      LAYER Metal2 ;
        RECT 252.375 0.000 252.575 2.475 ;
    END
  END ON[15]
  PIN ONB[15]
    ANTENNAGATEAREA 0.039000 ;
    PORT
      LAYER Metal2 ;
        RECT 252.925 0.000 253.125 2.475 ;
    END
  END ONB[15]
  PIN ON[14]
    ANTENNAGATEAREA 0.039000 ;
    PORT
      LAYER Metal2 ;
        RECT 254.375 0.000 254.575 2.475 ;
    END
  END ON[14]
  PIN ONB[14]
    ANTENNAGATEAREA 0.039000 ;
    PORT
      LAYER Metal2 ;
        RECT 254.925 0.000 255.125 2.475 ;
    END
  END ONB[14]
  PIN ON[13]
    ANTENNAGATEAREA 0.039000 ;
    PORT
      LAYER Metal2 ;
        RECT 256.375 0.000 256.575 2.475 ;
    END
  END ON[13]
  PIN ONB[13]
    ANTENNAGATEAREA 0.039000 ;
    PORT
      LAYER Metal2 ;
        RECT 256.925 0.000 257.125 2.475 ;
    END
  END ONB[13]
  PIN ON[12]
    ANTENNAGATEAREA 0.039000 ;
    PORT
      LAYER Metal2 ;
        RECT 258.375 0.000 258.575 2.475 ;
    END
  END ON[12]
  PIN ONB[12]
    ANTENNAGATEAREA 0.039000 ;
    PORT
      LAYER Metal2 ;
        RECT 258.925 0.000 259.125 2.475 ;
    END
  END ONB[12]
  PIN ON[11]
    ANTENNAGATEAREA 0.039000 ;
    PORT
      LAYER Metal2 ;
        RECT 260.375 0.000 260.575 2.475 ;
    END
  END ON[11]
  PIN ONB[11]
    ANTENNAGATEAREA 0.039000 ;
    PORT
      LAYER Metal2 ;
        RECT 260.925 0.000 261.125 2.475 ;
    END
  END ONB[11]
  PIN ON[10]
    ANTENNAGATEAREA 0.039000 ;
    PORT
      LAYER Metal2 ;
        RECT 262.375 0.000 262.575 2.475 ;
    END
  END ON[10]
  PIN ONB[10]
    ANTENNAGATEAREA 0.039000 ;
    PORT
      LAYER Metal2 ;
        RECT 262.925 0.000 263.125 2.475 ;
    END
  END ONB[10]
  PIN ON[9]
    ANTENNAGATEAREA 0.039000 ;
    PORT
      LAYER Metal2 ;
        RECT 264.375 0.000 264.575 2.475 ;
    END
  END ON[9]
  PIN EN[1]
    ANTENNAGATEAREA 0.039000 ;
    PORT
      LAYER Metal2 ;
        RECT 250.375 0.000 250.575 2.475 ;
    END
  END EN[1]
  PIN ENB[1]
    ANTENNAGATEAREA 0.039000 ;
    PORT
      LAYER Metal2 ;
        RECT 250.925 0.000 251.125 2.475 ;
    END
  END ENB[1]
  PIN ONB[9]
    ANTENNAGATEAREA 0.039000 ;
    PORT
      LAYER Metal2 ;
        RECT 264.925 0.000 265.125 2.475 ;
    END
  END ONB[9]
  PIN ON[8]
    ANTENNAGATEAREA 0.039000 ;
    PORT
      LAYER Metal2 ;
        RECT 266.375 0.000 266.575 2.475 ;
    END
  END ON[8]
  PIN ONB[8]
    ANTENNAGATEAREA 0.039000 ;
    PORT
      LAYER Metal2 ;
        RECT 266.925 0.000 267.125 2.475 ;
    END
  END ONB[8]
  PIN ON[7]
    ANTENNAGATEAREA 0.039000 ;
    PORT
      LAYER Metal2 ;
        RECT 268.375 0.000 268.575 2.475 ;
    END
  END ON[7]
  PIN ONB[7]
    ANTENNAGATEAREA 0.039000 ;
    PORT
      LAYER Metal2 ;
        RECT 268.925 0.000 269.125 2.475 ;
    END
  END ONB[7]
  PIN ON[6]
    ANTENNAGATEAREA 0.039000 ;
    PORT
      LAYER Metal2 ;
        RECT 270.375 0.000 270.575 2.475 ;
    END
  END ON[6]
  PIN ONB[6]
    ANTENNAGATEAREA 0.039000 ;
    PORT
      LAYER Metal2 ;
        RECT 270.925 0.000 271.125 2.475 ;
    END
  END ONB[6]
  PIN ON[5]
    ANTENNAGATEAREA 0.039000 ;
    PORT
      LAYER Metal2 ;
        RECT 272.375 0.000 272.575 2.475 ;
    END
  END ON[5]
  PIN ONB[5]
    ANTENNAGATEAREA 0.039000 ;
    PORT
      LAYER Metal2 ;
        RECT 272.925 0.000 273.125 2.475 ;
    END
  END ONB[5]
  PIN ON[4]
    ANTENNAGATEAREA 0.039000 ;
    PORT
      LAYER Metal2 ;
        RECT 274.375 0.000 274.575 2.475 ;
    END
  END ON[4]
  PIN ONB[4]
    ANTENNAGATEAREA 0.039000 ;
    PORT
      LAYER Metal2 ;
        RECT 274.925 0.000 275.125 2.475 ;
    END
  END ONB[4]
  PIN ON[3]
    ANTENNAGATEAREA 0.039000 ;
    PORT
      LAYER Metal2 ;
        RECT 276.375 0.000 276.575 2.475 ;
    END
  END ON[3]
  PIN ONB[3]
    ANTENNAGATEAREA 0.039000 ;
    PORT
      LAYER Metal2 ;
        RECT 276.925 0.000 277.125 2.475 ;
    END
  END ONB[3]
  PIN ON[2]
    ANTENNAGATEAREA 0.039000 ;
    PORT
      LAYER Metal2 ;
        RECT 278.375 0.000 278.575 2.475 ;
    END
  END ON[2]
  PIN ONB[2]
    ANTENNAGATEAREA 0.039000 ;
    PORT
      LAYER Metal2 ;
        RECT 278.925 0.000 279.125 2.475 ;
    END
  END ONB[2]
  PIN ON[1]
    ANTENNAGATEAREA 0.039000 ;
    PORT
      LAYER Metal2 ;
        RECT 280.375 0.000 280.575 2.475 ;
    END
  END ON[1]
  PIN ONB[1]
    ANTENNAGATEAREA 0.039000 ;
    PORT
      LAYER Metal2 ;
        RECT 280.925 0.000 281.125 2.475 ;
    END
  END ONB[1]
  PIN ON[0]
    ANTENNAGATEAREA 0.039000 ;
    PORT
      LAYER Metal2 ;
        RECT 282.375 0.000 282.575 2.475 ;
    END
  END ON[0]
  PIN ONB[0]
    ANTENNAGATEAREA 0.039000 ;
    PORT
      LAYER Metal2 ;
        RECT 282.925 0.000 283.125 2.475 ;
    END
  END ONB[0]
  PIN VbiasP[0]
    ANTENNAGATEAREA 119.723000 ;
    ANTENNADIFFAREA 5.814000 ;
    PORT
      LAYER Metal3 ;
        RECT 290.110 4.560 308.700 5.260 ;
    END
  END VbiasP[0]
  PIN VbiasP[1]
    ANTENNAGATEAREA 119.723000 ;
    ANTENNADIFFAREA 5.814000 ;
    PORT
      LAYER Metal3 ;
        RECT 222.220 8.480 308.700 9.180 ;
    END
  END VbiasP[1]
  PIN VbiasP[2]
    ANTENNAGATEAREA 119.723000 ;
    ANTENNADIFFAREA 5.814000 ;
    PORT
      LAYER Metal3 ;
        RECT 146.620 9.580 308.700 10.280 ;
    END
  END VbiasP[2]
  PIN VbiasP[3]
    ANTENNAGATEAREA 119.723000 ;
    ANTENNADIFFAREA 5.814000 ;
    PORT
      LAYER Metal3 ;
        RECT 71.020 10.680 308.700 11.380 ;
    END
  END VbiasP[3]
  PIN VbiasP[4]
    ANTENNAGATEAREA 119.723000 ;
    ANTENNADIFFAREA 5.814000 ;
    PORT
      LAYER Metal3 ;
        RECT 71.020 14.805 308.700 15.505 ;
    END
  END VbiasP[4]
  PIN VbiasP[5]
    ANTENNAGATEAREA 119.723000 ;
    ANTENNADIFFAREA 5.814000 ;
    PORT
      LAYER Metal3 ;
        RECT 146.620 15.905 308.700 16.605 ;
    END
  END VbiasP[5]
  PIN VbiasP[6]
    ANTENNAGATEAREA 119.723000 ;
    ANTENNADIFFAREA 5.814000 ;
    PORT
      LAYER Metal3 ;
        RECT 222.220 17.005 308.700 17.705 ;
    END
  END VbiasP[6]
  PIN VbiasP[7]
    ANTENNAGATEAREA 119.723000 ;
    ANTENNADIFFAREA 5.814000 ;
    PORT
      LAYER Metal3 ;
        RECT 290.110 20.930 308.700 21.630 ;
    END
  END VbiasP[7]
  PIN Iout
    ANTENNADIFFAREA 66.047997 ;
    PORT
      LAYER Metal3 ;
        RECT 308.000 12.745 308.700 13.445 ;
    END
  END Iout
  PIN VDD
    USE POWER ;
    PORT
      LAYER Metal5 ;
        RECT 0.000 0.000 308.700 11.810 ;
    END
  END VDD
  PIN VSS
    USE GROUND ;
    PORT
      LAYER Metal5 ;
        RECT 0.000 14.380 308.700 26.190 ;
    END
  END VSS
  OBS
      LAYER GatPoly ;
        RECT 3.265 -0.070 305.435 26.260 ;
      LAYER Metal1 ;
        RECT 0.000 0.000 308.700 26.190 ;
      LAYER Metal2 ;
        RECT 3.925 23.505 23.365 26.190 ;
        RECT 24.535 23.505 25.365 26.190 ;
        RECT 26.535 23.505 27.365 26.190 ;
        RECT 28.535 23.505 29.365 26.190 ;
        RECT 30.535 23.505 31.365 26.190 ;
        RECT 32.535 23.505 33.365 26.190 ;
        RECT 34.535 23.505 35.365 26.190 ;
        RECT 36.535 23.505 37.365 26.190 ;
        RECT 38.535 23.505 39.365 26.190 ;
        RECT 40.535 23.505 41.365 26.190 ;
        RECT 42.535 23.505 43.365 26.190 ;
        RECT 44.535 23.505 45.365 26.190 ;
        RECT 46.535 23.505 47.365 26.190 ;
        RECT 48.535 23.505 49.365 26.190 ;
        RECT 50.535 23.505 51.365 26.190 ;
        RECT 52.535 23.505 53.365 26.190 ;
        RECT 54.535 23.505 55.365 26.190 ;
        RECT 56.535 23.505 57.365 26.190 ;
        RECT 58.535 23.505 98.965 26.190 ;
        RECT 100.135 23.505 100.965 26.190 ;
        RECT 102.135 23.505 102.965 26.190 ;
        RECT 104.135 23.505 104.965 26.190 ;
        RECT 106.135 23.505 106.965 26.190 ;
        RECT 108.135 23.505 108.965 26.190 ;
        RECT 110.135 23.505 110.965 26.190 ;
        RECT 112.135 23.505 112.965 26.190 ;
        RECT 114.135 23.505 114.965 26.190 ;
        RECT 116.135 23.505 116.965 26.190 ;
        RECT 118.135 23.505 118.965 26.190 ;
        RECT 120.135 23.505 120.965 26.190 ;
        RECT 122.135 23.505 122.965 26.190 ;
        RECT 124.135 23.505 124.965 26.190 ;
        RECT 126.135 23.505 126.965 26.190 ;
        RECT 128.135 23.505 128.965 26.190 ;
        RECT 130.135 23.505 130.965 26.190 ;
        RECT 132.135 23.505 132.965 26.190 ;
        RECT 134.135 23.505 174.565 26.190 ;
        RECT 175.735 23.505 176.565 26.190 ;
        RECT 177.735 23.505 178.565 26.190 ;
        RECT 179.735 23.505 180.565 26.190 ;
        RECT 181.735 23.505 182.565 26.190 ;
        RECT 183.735 23.505 184.565 26.190 ;
        RECT 185.735 23.505 186.565 26.190 ;
        RECT 187.735 23.505 188.565 26.190 ;
        RECT 189.735 23.505 190.565 26.190 ;
        RECT 191.735 23.505 192.565 26.190 ;
        RECT 193.735 23.505 194.565 26.190 ;
        RECT 195.735 23.505 196.565 26.190 ;
        RECT 197.735 23.505 198.565 26.190 ;
        RECT 199.735 23.505 200.565 26.190 ;
        RECT 201.735 23.505 202.565 26.190 ;
        RECT 203.735 23.505 204.565 26.190 ;
        RECT 205.735 23.505 206.565 26.190 ;
        RECT 207.735 23.505 208.565 26.190 ;
        RECT 209.735 23.505 250.165 26.190 ;
        RECT 251.335 23.505 252.165 26.190 ;
        RECT 253.335 23.505 254.165 26.190 ;
        RECT 255.335 23.505 256.165 26.190 ;
        RECT 257.335 23.505 258.165 26.190 ;
        RECT 259.335 23.505 260.165 26.190 ;
        RECT 261.335 23.505 262.165 26.190 ;
        RECT 263.335 23.505 264.165 26.190 ;
        RECT 265.335 23.505 266.165 26.190 ;
        RECT 267.335 23.505 268.165 26.190 ;
        RECT 269.335 23.505 270.165 26.190 ;
        RECT 271.335 23.505 272.165 26.190 ;
        RECT 273.335 23.505 274.165 26.190 ;
        RECT 275.335 23.505 276.165 26.190 ;
        RECT 277.335 23.505 278.165 26.190 ;
        RECT 279.335 23.505 280.165 26.190 ;
        RECT 281.335 23.505 282.165 26.190 ;
        RECT 283.335 23.505 284.165 26.190 ;
        RECT 285.335 23.505 308.700 26.190 ;
        RECT 3.925 2.685 308.700 23.505 ;
        RECT 3.925 0.000 23.365 2.685 ;
        RECT 24.535 0.000 25.365 2.685 ;
        RECT 26.535 0.000 27.365 2.685 ;
        RECT 28.535 0.000 29.365 2.685 ;
        RECT 30.535 0.000 31.365 2.685 ;
        RECT 32.535 0.000 33.365 2.685 ;
        RECT 34.535 0.000 35.365 2.685 ;
        RECT 36.535 0.000 37.365 2.685 ;
        RECT 38.535 0.000 39.365 2.685 ;
        RECT 40.535 0.000 41.365 2.685 ;
        RECT 42.535 0.000 43.365 2.685 ;
        RECT 44.535 0.000 45.365 2.685 ;
        RECT 46.535 0.000 47.365 2.685 ;
        RECT 48.535 0.000 49.365 2.685 ;
        RECT 50.535 0.000 51.365 2.685 ;
        RECT 52.535 0.000 53.365 2.685 ;
        RECT 54.535 0.000 55.365 2.685 ;
        RECT 56.535 0.000 57.365 2.685 ;
        RECT 58.535 0.000 98.965 2.685 ;
        RECT 100.135 0.000 100.965 2.685 ;
        RECT 102.135 0.000 102.965 2.685 ;
        RECT 104.135 0.000 104.965 2.685 ;
        RECT 106.135 0.000 106.965 2.685 ;
        RECT 108.135 0.000 108.965 2.685 ;
        RECT 110.135 0.000 110.965 2.685 ;
        RECT 112.135 0.000 112.965 2.685 ;
        RECT 114.135 0.000 114.965 2.685 ;
        RECT 116.135 0.000 116.965 2.685 ;
        RECT 118.135 0.000 118.965 2.685 ;
        RECT 120.135 0.000 120.965 2.685 ;
        RECT 122.135 0.000 122.965 2.685 ;
        RECT 124.135 0.000 124.965 2.685 ;
        RECT 126.135 0.000 126.965 2.685 ;
        RECT 128.135 0.000 128.965 2.685 ;
        RECT 130.135 0.000 130.965 2.685 ;
        RECT 132.135 0.000 132.965 2.685 ;
        RECT 134.135 0.000 174.565 2.685 ;
        RECT 175.735 0.000 176.565 2.685 ;
        RECT 177.735 0.000 178.565 2.685 ;
        RECT 179.735 0.000 180.565 2.685 ;
        RECT 181.735 0.000 182.565 2.685 ;
        RECT 183.735 0.000 184.565 2.685 ;
        RECT 185.735 0.000 186.565 2.685 ;
        RECT 187.735 0.000 188.565 2.685 ;
        RECT 189.735 0.000 190.565 2.685 ;
        RECT 191.735 0.000 192.565 2.685 ;
        RECT 193.735 0.000 194.565 2.685 ;
        RECT 195.735 0.000 196.565 2.685 ;
        RECT 197.735 0.000 198.565 2.685 ;
        RECT 199.735 0.000 200.565 2.685 ;
        RECT 201.735 0.000 202.565 2.685 ;
        RECT 203.735 0.000 204.565 2.685 ;
        RECT 205.735 0.000 206.565 2.685 ;
        RECT 207.735 0.000 208.565 2.685 ;
        RECT 209.735 0.000 250.165 2.685 ;
        RECT 251.335 0.000 252.165 2.685 ;
        RECT 253.335 0.000 254.165 2.685 ;
        RECT 255.335 0.000 256.165 2.685 ;
        RECT 257.335 0.000 258.165 2.685 ;
        RECT 259.335 0.000 260.165 2.685 ;
        RECT 261.335 0.000 262.165 2.685 ;
        RECT 263.335 0.000 264.165 2.685 ;
        RECT 265.335 0.000 266.165 2.685 ;
        RECT 267.335 0.000 268.165 2.685 ;
        RECT 269.335 0.000 270.165 2.685 ;
        RECT 271.335 0.000 272.165 2.685 ;
        RECT 273.335 0.000 274.165 2.685 ;
        RECT 275.335 0.000 276.165 2.685 ;
        RECT 277.335 0.000 278.165 2.685 ;
        RECT 279.335 0.000 280.165 2.685 ;
        RECT 281.335 0.000 282.165 2.685 ;
        RECT 283.335 0.000 284.165 2.685 ;
        RECT 285.335 0.000 308.700 2.685 ;
      LAYER Metal3 ;
        RECT 0.000 21.840 308.700 26.190 ;
        RECT 0.000 20.720 289.900 21.840 ;
        RECT 0.000 17.915 308.700 20.720 ;
        RECT 0.000 16.815 222.010 17.915 ;
        RECT 0.000 15.715 146.410 16.815 ;
        RECT 0.000 14.595 70.810 15.715 ;
        RECT 0.000 13.655 308.700 14.595 ;
        RECT 0.000 12.535 307.790 13.655 ;
        RECT 0.000 11.590 308.700 12.535 ;
        RECT 0.000 10.470 70.810 11.590 ;
        RECT 0.000 9.370 146.410 10.470 ;
        RECT 0.000 8.270 222.010 9.370 ;
        RECT 0.000 5.470 308.700 8.270 ;
        RECT 0.000 4.350 289.900 5.470 ;
        RECT 0.000 0.000 308.700 4.350 ;
      LAYER Metal4 ;
        RECT 22.050 0.000 286.650 26.190 ;
  END
END dac4x32module
END LIBRARY

